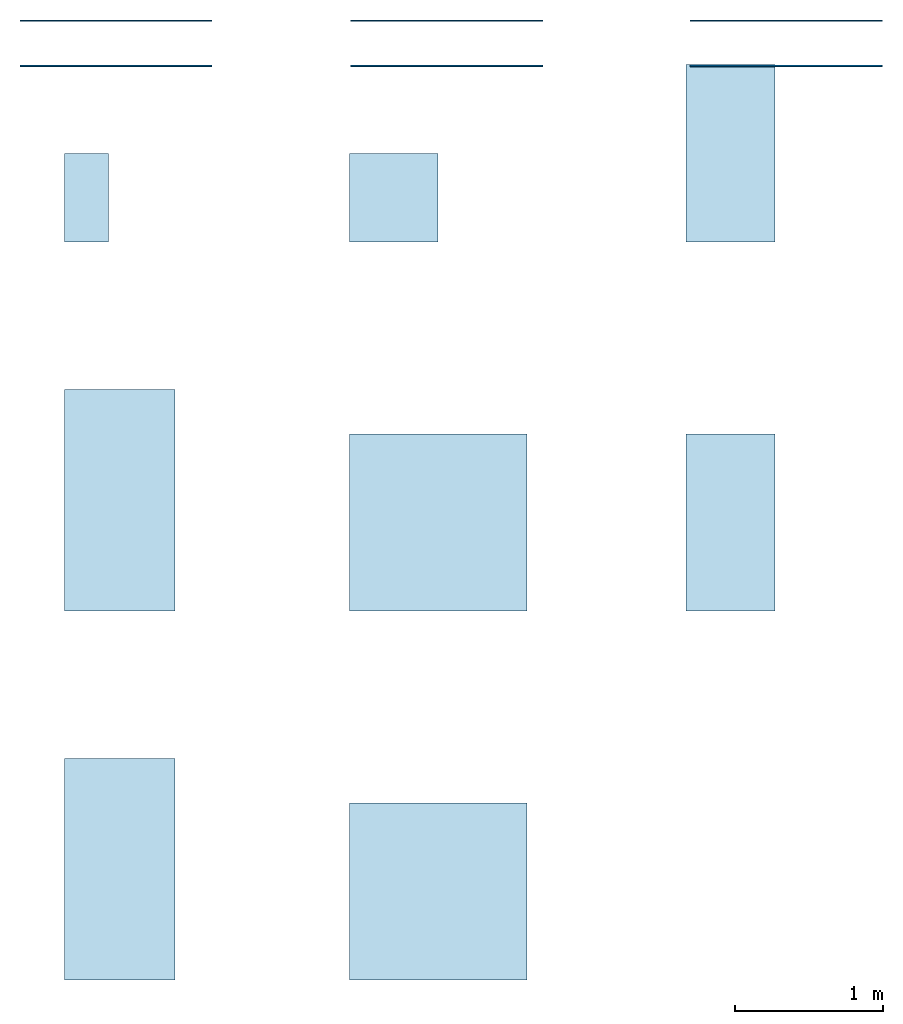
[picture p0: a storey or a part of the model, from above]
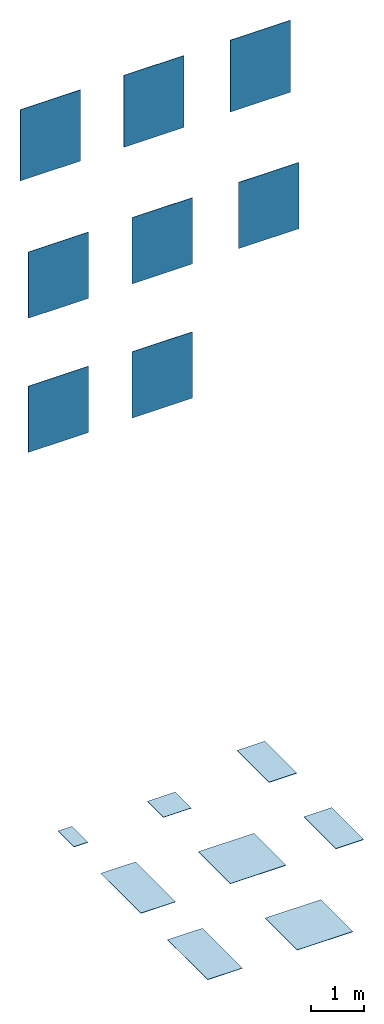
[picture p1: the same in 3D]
Properties of the parts of a building model (IFC2X3)

# File
Description: ViewDefinition [CoordinationView_V2.0], RevitIdentifiers [VersionGUID: b3245cd9-b47f-4d14-973e-95603488568c, NumberOfSaves: 367], CoordinateReference [CoordinateBase: Shared Coordinates, ProjectSite: Internal]
File name: Project Number
Time: 2025-03-27T15:56:52+01:00
Written by: ODA SDAI 24.3
Made in: Autodesk Revit 24.1.11.26 (ENU) - IFC 24.1.11.26

# IfcProject, Project Number
LongName: Refin-Blended; Phase: Project Status

# IfcSite, Default
RefLatitude: 51, 30, 0, 549316; RefLongitude: 0, -7, -34, -450321; RefElevation: 0 mm

# IfcBuilding
Pset_BuildingCommon - NumberOfStoreys: 1

# IfcBuildingStorey: Level:Circle Head - Project Datum (2)
Pset_AirSideSystemInformation - sets with these values: 2
Name | LongName = Name | Elevation (mm)
Level 0 | Level 0 | 0
Level 1 | Level 1 | 4000

# IfcSlab: Floor:Floor_Tiles_Refin-Etherea-Sand-120x120 RJ67, Floor:Floor_Tiles_Refin-Etherea-Sand-120x120 RJ67:357631
In: Level 0
Type - PredefinedType: FLOOR; Material: Etherea-Sand-120x120 RJ67 9 mm, <Unnamed> 1 mm
Type - Pset_ConcreteElementGeneral - FireRating: INERT
Type - Pset_ElementShading - Color: MEDIUM BEIGE
Type - Pset_FireRatingProperties - SurfaceSpreadOfFlame: INERT
Type - Pset_ManufacturerOccurrence - BarCode: N/A; SerialNumber: N/A
Type - Pset_ManufacturerTypeInformation - ArticleNumber: RJ67; ModelReference: RJ67; ModelLabel: SAND R 120X120; Manufacturer: info@refin.it; ProductionYear: N/A
Type - Pset_PrecastConcreteElementGeneral - SerialNumber: N/A
Type - Pset_ProductRequirements - Name: Etherea_Sand_120X120 R; Category: Pr_35_93_96_19:Ceramic tiles
Type - Pset_QuantityTakeOff - Reference: N/A
Type - Pset_ReinforcementBarPitchOfSlab - Description: PORCELAIN STONEWARE TILE; Reference: N/A
Type - Pset_SlabCommon - Reference: N/A; IsExternal: no; AcousticRating: N/A; FireRating: INERT; SurfaceSpreadOfFlame: INERT
Type - Pset_Warranty - WarrantyContent: N/A; Exclusions: N/A
Pset_QuantityTakeOff - sets with these values: 2
Pset_SlabCommon - LoadBearing: no; PitchAngle: 0 deg

# IfcSlab: Floor:Floor_Tiles_Refin-Etherea-Sand-30x60 RJ93, Floor:Floor_Tiles_Refin-Etherea-Sand-30x60 RJ93:304668
In: Level 0
Type - PredefinedType: FLOOR; Material: Etherea-Sand-30x60 RJ93 9 mm, <Unnamed> 1 mm
Type - Pset_ConcreteElementGeneral - FireRating: INERT
Type - Pset_ElementShading - Color: MEDIUM BEIGE
Type - Pset_FireRatingProperties - SurfaceSpreadOfFlame: INERT
Type - Pset_ManufacturerOccurrence - BarCode: N/A; SerialNumber: N/A
Type - Pset_ManufacturerTypeInformation - ArticleNumber: RJ93; ModelReference: RJ93; ModelLabel: SAND R 30X60; Manufacturer: info@refin.it; ProductionYear: N/A
Type - Pset_PrecastConcreteElementGeneral - SerialNumber: N/A
Type - Pset_ProductRequirements - Name: Etherea_Sand_30X60 R; Category: Pr_35_93_96_19:Ceramic tiles
Type - Pset_QuantityTakeOff - Reference: N/A
Type - Pset_ReinforcementBarPitchOfSlab - Description: PORCELAIN STONEWARE TILE; Reference: N/A
Type - Pset_SlabCommon - Reference: N/A; IsExternal: no; AcousticRating: N/A; FireRating: INERT; SurfaceSpreadOfFlame: INERT
Type - Pset_Warranty - WarrantyContent: N/A; Exclusions: N/A
Pset_QuantityTakeOff - sets with these values: 2
Pset_SlabCommon - LoadBearing: no; PitchAngle: 0 deg

# IfcSlab: Floor:Floor_Tiles_Refin-Etherea-Sand-60x120 RJ73, Floor:Floor_Tiles_Refin-Etherea-Sand-60x120 RJ73:357441
In: Level 0
Type - PredefinedType: FLOOR; Material: Etherea-Sand-60x120 RJ73 9 mm, <Unnamed> 1 mm
Type - Pset_ConcreteElementGeneral - FireRating: INERT
Type - Pset_ElementShading - Color: MEDIUM BEIGE
Type - Pset_FireRatingProperties - SurfaceSpreadOfFlame: INERT
Type - Pset_ManufacturerOccurrence - BarCode: N/A; SerialNumber: N/A
Type - Pset_ManufacturerTypeInformation - ArticleNumber: RJ73; ModelReference: RJ73; ModelLabel: SAND R 60X120; Manufacturer: info@refin.it; ProductionYear: N/A
Type - Pset_PrecastConcreteElementGeneral - SerialNumber: N/A
Type - Pset_ProductRequirements - Name: Etherea_Sand_60X120 R; Category: Pr_35_93_96_19:Ceramic tiles
Type - Pset_QuantityTakeOff - Reference: N/A
Type - Pset_ReinforcementBarPitchOfSlab - Description: PORCELAIN STONEWARE TILE; Reference: N/A
Type - Pset_SlabCommon - Reference: N/A; IsExternal: no; AcousticRating: N/A; FireRating: INERT; SurfaceSpreadOfFlame: INERT
Type - Pset_Warranty - WarrantyContent: N/A; Exclusions: N/A
Pset_QuantityTakeOff - sets with these values: 2
Pset_SlabCommon - LoadBearing: no; PitchAngle: 0 deg

# IfcSlab: Floor:Floor_Tiles_Refin-Etherea-Sand-60x60 RJ88, Floor:Floor_Tiles_Refin-Etherea-Sand-60x60 RJ88:357245
In: Level 0
Type - PredefinedType: FLOOR; Material: Etherea-Sand-60x60 RJ88 9 mm, <Unnamed> 1 mm
Type - Pset_ConcreteElementGeneral - FireRating: INERT
Type - Pset_ElementShading - Color: MEDIUM BEIGE
Type - Pset_FireRatingProperties - SurfaceSpreadOfFlame: INERT
Type - Pset_ManufacturerOccurrence - BarCode: N/A; SerialNumber: N/A
Type - Pset_ManufacturerTypeInformation - ArticleNumber: RJ88; ModelReference: RJ88; ModelLabel: SAND R 60X60; Manufacturer: info@refin.it; ProductionYear: N/A
Type - Pset_PrecastConcreteElementGeneral - SerialNumber: N/A
Type - Pset_ProductRequirements - Name: Etherea_Sand_60X60 R; Category: Pr_35_93_96_19:Ceramic tiles
Type - Pset_QuantityTakeOff - Reference: N/A
Type - Pset_ReinforcementBarPitchOfSlab - Description: PORCELAIN STONEWARE TILE; Reference: N/A
Type - Pset_SlabCommon - Reference: N/A; IsExternal: no; AcousticRating: N/A; FireRating: INERT; SurfaceSpreadOfFlame: INERT
Type - Pset_Warranty - WarrantyContent: N/A; Exclusions: N/A
Pset_QuantityTakeOff - sets with these values: 2
Pset_SlabCommon - LoadBearing: no; PitchAngle: 0 deg

# IfcSlab: Floor:Floor_Tiles_Refin-Etherea-Sand-75x150 RK17, Floor:Floor_Tiles_Refin-Etherea-Sand-75x150 RK17:357623
In: Level 0
Type - PredefinedType: FLOOR; Material: Etherea-Sand-75x150 RK17 9 mm, <Unnamed> 1 mm
Type - Pset_ConcreteElementGeneral - FireRating: INERT
Type - Pset_ElementShading - Color: MEDIUM BEIGE
Type - Pset_FireRatingProperties - SurfaceSpreadOfFlame: INERT
Type - Pset_ManufacturerOccurrence - BarCode: N/A; SerialNumber: N/A
Type - Pset_ManufacturerTypeInformation - ArticleNumber: RK17; ModelReference: RK17; ModelLabel: SAND R 75X150; Manufacturer: info@refin.it; ProductionYear: N/A
Type - Pset_PrecastConcreteElementGeneral - SerialNumber: N/A
Type - Pset_ProductRequirements - Name: Etherea_Sand_75X150 R; Category: Pr_35_93_96_19:Ceramic tiles
Type - Pset_QuantityTakeOff - Reference: N/A
Type - Pset_ReinforcementBarPitchOfSlab - Description: PORCELAIN STONEWARE TILE; Reference: N/A
Type - Pset_SlabCommon - Reference: N/A; IsExternal: no; AcousticRating: N/A; FireRating: INERT; SurfaceSpreadOfFlame: INERT
Type - Pset_Warranty - WarrantyContent: N/A; Exclusions: N/A
Pset_QuantityTakeOff - sets with these values: 2
Pset_SlabCommon - LoadBearing: no; PitchAngle: 0 deg

# IfcSlab: Floor:Floor_Tiles_Refin-Etherea-Sand-C2-GRIP-60x120 RN18, Floor:Floor_Tiles_Refin-Etherea-Sand-C2-GRIP-60x120 RN18:357639
In: Level 0
Type - PredefinedType: FLOOR; Material: Etherea-Sand-C2-GRIP-60x120 RN18 9 mm, <Unnamed> 1 mm
Type - Pset_ConcreteElementGeneral - FireRating: INERT
Type - Pset_ElementShading - Color: MEDIUM BEIGE
Type - Pset_FireRatingProperties - SurfaceSpreadOfFlame: INERT
Type - Pset_ManufacturerOccurrence - BarCode: N/A; SerialNumber: N/A
Type - Pset_ManufacturerTypeInformation - ArticleNumber: RN18; ModelReference: RN18; ModelLabel: SAND C2 GRIP R 60X120; Manufacturer: info@refin.it; ProductionYear: N/A
Type - Pset_PrecastConcreteElementGeneral - SerialNumber: N/A
Type - Pset_ProductRequirements - Name: Etherea_Sand_C2_GRIP_60X120 R; Category: Pr_35_93_96_19:Ceramic tiles
Type - Pset_QuantityTakeOff - Reference: N/A
Type - Pset_ReinforcementBarPitchOfSlab - Description: PORCELAIN STONEWARE TILE; Reference: N/A
Type - Pset_SlabCommon - Reference: N/A; IsExternal: no; AcousticRating: N/A; FireRating: INERT; SurfaceSpreadOfFlame: INERT
Type - Pset_Warranty - WarrantyContent: N/A; Exclusions: N/A
Pset_QuantityTakeOff - sets with these values: 2
Pset_SlabCommon - LoadBearing: no; PitchAngle: 0 deg

# IfcSlab: Floor:Floor_Tiles_Refin-Etherea-Sand-Lucido-120x120 RJ65, Floor:Floor_Tiles_Refin-Etherea-Sand-Lucido-120x120 RJ65:361557
In: Level 0
Type - PredefinedType: FLOOR; Material: Etherea-Sand-Lucido-120x120 RJ65 9 mm, <Unnamed> 1 mm
Type - Pset_ConcreteElementGeneral - FireRating: INERT
Type - Pset_ElementShading - Color: MEDIUM BEIGE
Type - Pset_FireRatingProperties - SurfaceSpreadOfFlame: INERT
Type - Pset_ManufacturerOccurrence - BarCode: N/A; SerialNumber: N/A
Type - Pset_ManufacturerTypeInformation - ArticleNumber: RJ65; ModelReference: RJ65; ModelLabel: SAND LUCIDO R 120X120; Manufacturer: info@refin.it; ProductionYear: N/A
Type - Pset_PrecastConcreteElementGeneral - SerialNumber: N/A
Type - Pset_ProductRequirements - Name: Etherea_Sand_Lucido_120X120 R; Category: Pr_35_93_96_19:Ceramic tiles
Type - Pset_QuantityTakeOff - Reference: N/A
Type - Pset_ReinforcementBarPitchOfSlab - Description: PORCELAIN STONEWARE TILE; Reference: N/A
Type - Pset_SlabCommon - Reference: N/A; IsExternal: no; AcousticRating: N/A; FireRating: INERT; SurfaceSpreadOfFlame: INERT
Type - Pset_Warranty - WarrantyContent: N/A; Exclusions: N/A
Pset_QuantityTakeOff - sets with these values: 2
Pset_SlabCommon - LoadBearing: no; PitchAngle: 0 deg

# IfcSlab: Floor:Floor_Tiles_Refin-Etherea-Sand-Lucido-75x150 RK22, Floor:Floor_Tiles_Refin-Etherea-Sand-Lucido-75x150 RK22:361417
In: Level 0
Type - PredefinedType: FLOOR; Material: Etherea-Sand-Lucido-75x150 RK22 9 mm, <Unnamed> 1 mm
Type - Pset_ConcreteElementGeneral - FireRating: INERT
Type - Pset_ElementShading - Color: MEDIUM BEIGE
Type - Pset_FireRatingProperties - SurfaceSpreadOfFlame: INERT
Type - Pset_ManufacturerOccurrence - BarCode: N/A; SerialNumber: N/A
Type - Pset_ManufacturerTypeInformation - ArticleNumber: RK22; ModelReference: RK22; ModelLabel: SAND LUCIDO R 75X150; Manufacturer: info@refin.it; ProductionYear: N/A
Type - Pset_PrecastConcreteElementGeneral - SerialNumber: N/A
Type - Pset_ProductRequirements - Name: Etherea_Sand_Lucido_75X150 R; Category: Pr_35_93_96_19:Ceramic tiles
Type - Pset_QuantityTakeOff - Reference: N/A
Type - Pset_ReinforcementBarPitchOfSlab - Description: PORCELAIN STONEWARE TILE; Reference: N/A
Type - Pset_SlabCommon - Reference: N/A; IsExternal: no; AcousticRating: N/A; FireRating: INERT; SurfaceSpreadOfFlame: INERT
Type - Pset_Warranty - WarrantyContent: N/A; Exclusions: N/A
Pset_QuantityTakeOff - sets with these values: 2
Pset_SlabCommon - LoadBearing: no; PitchAngle: 0 deg

# IfcWallStandardCase: Basic Wall:Wall_Tiles_Refin-Etherea-Sand-120x120 RJ67, Basic Wall:Wall_Tiles_Refin-Etherea-Sand-120x120 RJ67:335490
In: Level 0
Type - PredefinedType: STANDARD; Material: <Unnamed> 1 mm, Etherea-Sand-120x120 RJ67 9 mm
Type - Pset_ElementShading - Color: MEDIUM BEIGE
Type - Pset_FireRatingProperties - SurfaceSpreadOfFlame: INERT
Type - Pset_ManufacturerOccurrence - BarCode: N/A; SerialNumber: N/A
Type - Pset_ManufacturerTypeInformation - ArticleNumber: RJ67; ModelReference: RJ67; ModelLabel: SAND R 120X120; Manufacturer: info@refin.it; ProductionYear: N/A
Type - Pset_PrecastConcreteElementGeneral - SerialNumber: N/A
Type - Pset_ProductRequirements - Name: Etherea_Sand_120X120 R; Category: Pr_35_93_96_19:Ceramic tiles
Type - Pset_QuantityTakeOff - Reference: N/A
Type - Pset_ReinforcementBarPitchOfWall - Description: PORCELAIN STONEWARE TILE; Reference: N/A
Type - Pset_WallCommon - Reference: N/A; IsExternal: no; AcousticRating: N/A; SurfaceSpreadOfFlame: INERT
Type - Pset_Warranty - WarrantyContent: N/A; Exclusions: N/A
Pset_QuantityTakeOff - sets with these values: 2
Pset_WallCommon - LoadBearing: no; ExtendToStructure: no

# IfcWallStandardCase: Basic Wall:Wall_Tiles_Refin-Etherea-Sand-30x60 RJ93, Basic Wall:Wall_Tiles_Refin-Etherea-Sand-30x60 RJ93:334895
In: Level 0
Type - PredefinedType: STANDARD; Material: <Unnamed> 1 mm, Etherea-Sand-30x60 RJ93 9 mm
Type - Pset_ElementShading - Color: MEDIUM BEIGE
Type - Pset_FireRatingProperties - SurfaceSpreadOfFlame: INERT
Type - Pset_ManufacturerOccurrence - BarCode: N/A; SerialNumber: N/A
Type - Pset_ManufacturerTypeInformation - ArticleNumber: RJ93; ModelReference: RJ93; ModelLabel: SAND R 30X60; Manufacturer: info@refin.it; ProductionYear: N/A
Type - Pset_PrecastConcreteElementGeneral - SerialNumber: N/A
Type - Pset_ProductRequirements - Name: Etherea_Sand_30X60 R; Category: Pr_35_93_96_19:Ceramic tiles
Type - Pset_QuantityTakeOff - Reference: N/A
Type - Pset_ReinforcementBarPitchOfWall - Description: PORCELAIN STONEWARE TILE; Reference: N/A
Type - Pset_WallCommon - Reference: N/A; IsExternal: no; AcousticRating: N/A; SurfaceSpreadOfFlame: INERT
Type - Pset_Warranty - WarrantyContent: N/A; Exclusions: N/A
Pset_QuantityTakeOff - sets with these values: 2
Pset_WallCommon - LoadBearing: no; ExtendToStructure: no

# IfcWallStandardCase: Basic Wall:Wall_Tiles_Refin-Etherea-Sand-60x120 RJ73, Basic Wall:Wall_Tiles_Refin-Etherea-Sand-60x120 RJ73:334553
In: Level 0
Type - PredefinedType: STANDARD; Material: <Unnamed> 1 mm, Etherea-Sand-60x120 RJ73 9 mm
Type - Pset_ElementShading - Color: MEDIUM BEIGE
Type - Pset_FireRatingProperties - SurfaceSpreadOfFlame: INERT
Type - Pset_ManufacturerOccurrence - BarCode: N/A; SerialNumber: N/A
Type - Pset_ManufacturerTypeInformation - ArticleNumber: RJ73; ModelReference: RJ73; ModelLabel: SAND R 60X120; Manufacturer: info@refin.it; ProductionYear: N/A
Type - Pset_PrecastConcreteElementGeneral - SerialNumber: N/A
Type - Pset_ProductRequirements - Name: Etherea_Sand_60X120 R; Category: Pr_35_93_96_19:Ceramic tiles
Type - Pset_QuantityTakeOff - Reference: N/A
Type - Pset_ReinforcementBarPitchOfWall - Description: PORCELAIN STONEWARE TILE; Reference: N/A
Type - Pset_WallCommon - Reference: N/A; IsExternal: no; AcousticRating: N/A; SurfaceSpreadOfFlame: INERT
Type - Pset_Warranty - WarrantyContent: N/A; Exclusions: N/A
Pset_QuantityTakeOff - sets with these values: 2
Pset_WallCommon - LoadBearing: no; ExtendToStructure: no

# IfcWallStandardCase: Basic Wall:Wall_Tiles_Refin-Etherea-Sand-60x60 RJ88, Basic Wall:Wall_Tiles_Refin-Etherea-Sand-60x60 RJ88:333696
In: Level 0
Type - PredefinedType: STANDARD; Material: <Unnamed> 1 mm, Etherea-Sand-60x60 RJ88 9 mm
Type - Pset_ElementShading - Color: MEDIUM BEIGE
Type - Pset_FireRatingProperties - SurfaceSpreadOfFlame: INERT
Type - Pset_ManufacturerOccurrence - BarCode: N/A; SerialNumber: N/A
Type - Pset_ManufacturerTypeInformation - ArticleNumber: RJ88; ModelReference: RJ88; ModelLabel: SAND R 60X60; Manufacturer: info@refin.it; ProductionYear: N/A
Type - Pset_PrecastConcreteElementGeneral - SerialNumber: N/A
Type - Pset_ProductRequirements - Name: Etherea_Sand_60X60 R; Category: Pr_35_93_96_19:Ceramic tiles
Type - Pset_QuantityTakeOff - Reference: N/A
Type - Pset_ReinforcementBarPitchOfWall - Description: PORCELAIN STONEWARE TILE; Reference: N/A
Type - Pset_WallCommon - Reference: N/A; IsExternal: no; AcousticRating: N/A; SurfaceSpreadOfFlame: INERT
Type - Pset_Warranty - WarrantyContent: N/A; Exclusions: N/A
Pset_QuantityTakeOff - sets with these values: 2
Pset_WallCommon - LoadBearing: no; ExtendToStructure: no

# IfcWallStandardCase: Basic Wall:Wall_Tiles_Refin-Etherea-Sand-75x150 RK17, Basic Wall:Wall_Tiles_Refin-Etherea-Sand-75x150 RK17:335038
In: Level 0
Type - PredefinedType: STANDARD; Material: <Unnamed> 1 mm, Etherea-Sand-75x150 RK17 9 mm
Type - Pset_ElementShading - Color: MEDIUM BEIGE
Type - Pset_FireRatingProperties - SurfaceSpreadOfFlame: INERT
Type - Pset_ManufacturerOccurrence - BarCode: N/A; SerialNumber: N/A
Type - Pset_ManufacturerTypeInformation - ArticleNumber: RK17; ModelReference: RK17; ModelLabel: SAND R 75X150; Manufacturer: info@refin.it; ProductionYear: N/A
Type - Pset_PrecastConcreteElementGeneral - SerialNumber: N/A
Type - Pset_ProductRequirements - Name: Etherea_Sand_75X150 R; Category: Pr_35_93_96_19:Ceramic tiles
Type - Pset_QuantityTakeOff - Reference: N/A
Type - Pset_ReinforcementBarPitchOfWall - Description: PORCELAIN STONEWARE TILE; Reference: N/A
Type - Pset_WallCommon - Reference: N/A; IsExternal: no; AcousticRating: N/A; SurfaceSpreadOfFlame: INERT
Type - Pset_Warranty - WarrantyContent: N/A; Exclusions: N/A
Pset_QuantityTakeOff - sets with these values: 2
Pset_WallCommon - LoadBearing: no; ExtendToStructure: no

# IfcWallStandardCase: Basic Wall:Wall_Tiles_Refin-Etherea-Sand-C2-GRIP-60x120 RN18, Basic Wall:Wall_Tiles_Refin-Etherea-Sand-C2-GRIP-60x120 RN18:335882
In: Level 0
Type - PredefinedType: STANDARD; Material: <Unnamed> 1 mm, Etherea-Sand-C2-GRIP-60x120 RN18 9 mm
Type - Pset_ElementShading - Color: MEDIUM BEIGE
Type - Pset_FireRatingProperties - SurfaceSpreadOfFlame: INERT
Type - Pset_ManufacturerOccurrence - BarCode: N/A; SerialNumber: N/A
Type - Pset_ManufacturerTypeInformation - ArticleNumber: RN18; ModelReference: RN18; ModelLabel: SAND C2 GRIP R 60X120; Manufacturer: info@refin.it; ProductionYear: N/A
Type - Pset_PrecastConcreteElementGeneral - SerialNumber: N/A
Type - Pset_ProductRequirements - Name: Etherea_Sand_C2_GRIP_60X120 R; Category: Pr_35_93_96_19:Ceramic tiles
Type - Pset_QuantityTakeOff - Reference: N/A
Type - Pset_ReinforcementBarPitchOfWall - Description: PORCELAIN STONEWARE TILE; Reference: N/A
Type - Pset_WallCommon - Reference: N/A; IsExternal: no; AcousticRating: N/A; SurfaceSpreadOfFlame: INERT
Type - Pset_Warranty - WarrantyContent: N/A; Exclusions: N/A
Pset_QuantityTakeOff - sets with these values: 2
Pset_WallCommon - LoadBearing: no; ExtendToStructure: no

# IfcWallStandardCase: Basic Wall:Wall_Tiles_Refin-Etherea-Sand-Lucido-120x120 RJ65, Basic Wall:Wall_Tiles_Refin-Etherea-Sand-Lucido-120x120 RJ65:352457
In: Level 0
Type - PredefinedType: STANDARD; Material: <Unnamed> 1 mm, Etherea-Sand-Lucido-120x120 RJ65 9 mm
Type - Pset_ElementShading - Color: MEDIUM BEIGE
Type - Pset_FireRatingProperties - SurfaceSpreadOfFlame: INERT
Type - Pset_ManufacturerOccurrence - BarCode: N/A; SerialNumber: N/A
Type - Pset_ManufacturerTypeInformation - ArticleNumber: RJ65; ModelReference: RJ65; ModelLabel: SAND LUCIDO R 120X120; Manufacturer: info@refin.it; ProductionYear: N/A
Type - Pset_PrecastConcreteElementGeneral - SerialNumber: N/A
Type - Pset_ProductRequirements - Name: Etherea_Sand_Lucido_120X120 R; Category: Pr_35_93_96_19:Ceramic tiles
Type - Pset_QuantityTakeOff - Reference: N/A
Type - Pset_ReinforcementBarPitchOfWall - Description: PORCELAIN STONEWARE TILE; Reference: N/A
Type - Pset_WallCommon - Reference: N/A; IsExternal: no; AcousticRating: N/A; SurfaceSpreadOfFlame: INERT
Type - Pset_Warranty - WarrantyContent: N/A; Exclusions: N/A
Pset_QuantityTakeOff - sets with these values: 2
Pset_WallCommon - LoadBearing: no; ExtendToStructure: no

# IfcWallStandardCase: Basic Wall:Wall_Tiles_Refin-Etherea-Sand-Lucido-75x150 RK22, Basic Wall:Wall_Tiles_Refin-Etherea-Sand-Lucido-75x150 RK22:352136
In: Level 0
Type - PredefinedType: STANDARD; Material: <Unnamed> 1 mm, Etherea-Sand-Lucido-75x150 RK22 9 mm
Type - Pset_ElementShading - Color: MEDIUM BEIGE
Type - Pset_FireRatingProperties - SurfaceSpreadOfFlame: INERT
Type - Pset_ManufacturerOccurrence - BarCode: N/A; SerialNumber: N/A
Type - Pset_ManufacturerTypeInformation - ArticleNumber: RK22; ModelReference: RK22; ModelLabel: SAND LUCIDO R 75X150; Manufacturer: info@refin.it; ProductionYear: N/A
Type - Pset_PrecastConcreteElementGeneral - SerialNumber: N/A
Type - Pset_ProductRequirements - Name: Etherea_Sand_Lucido_75X150 R; Category: Pr_35_93_96_19:Ceramic tiles
Type - Pset_QuantityTakeOff - Reference: N/A
Type - Pset_ReinforcementBarPitchOfWall - Description: PORCELAIN STONEWARE TILE; Reference: N/A
Type - Pset_WallCommon - Reference: N/A; IsExternal: no; AcousticRating: N/A; SurfaceSpreadOfFlame: INERT
Type - Pset_Warranty - WarrantyContent: N/A; Exclusions: N/A
Pset_QuantityTakeOff - sets with these values: 2
Pset_WallCommon - LoadBearing: no; ExtendToStructure: no
